VERSION 5.7 ;
  NOWIREEXTENSIONATPIN ON ;
  DIVIDERCHAR "/" ;
  BUSBITCHARS "[]" ;
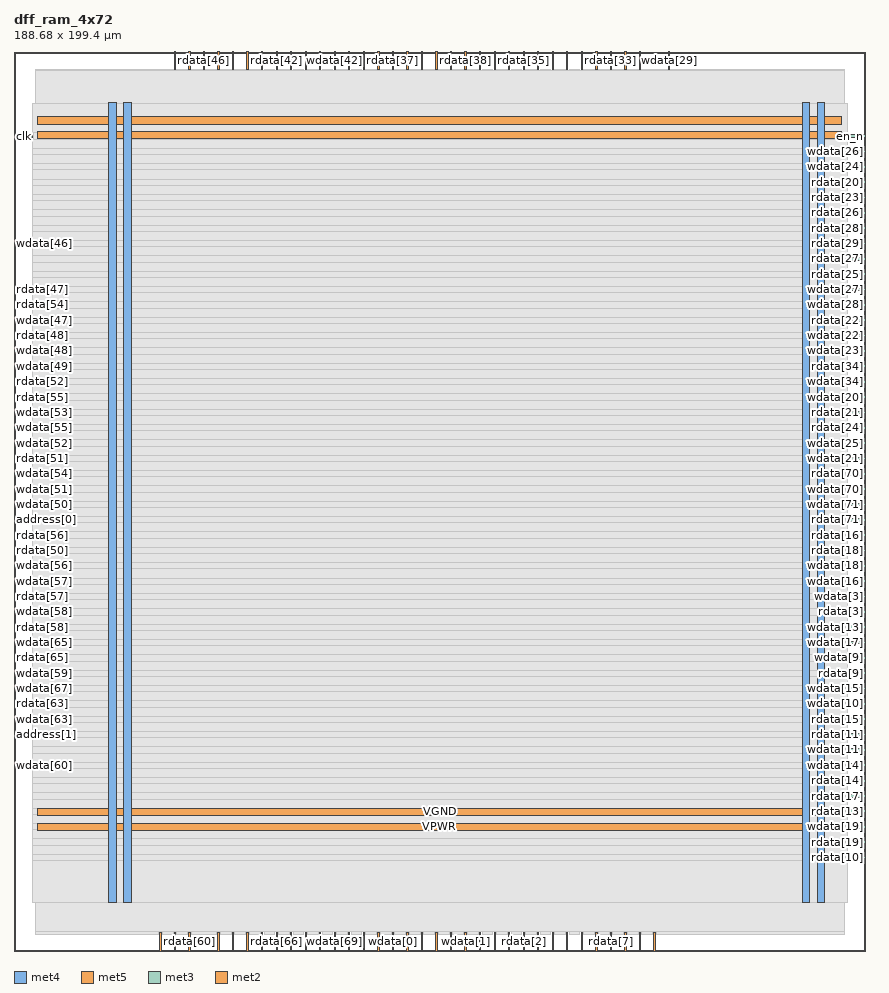
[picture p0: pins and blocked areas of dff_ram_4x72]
MACRO dff_ram_4x72
  CLASS BLOCK ;
  FOREIGN dff_ram_4x72 ;
  ORIGIN 0.000 0.000 ;
  SIZE 188.680 BY 199.400 ;
  PIN VGND
    DIRECTION INOUT ;
    USE GROUND ;
    PORT
      LAYER met4 ;
        RECT 24.340 10.640 25.940 187.920 ;
    END
    PORT
      LAYER met4 ;
        RECT 177.940 10.640 179.540 187.920 ;
    END
    PORT
      LAYER met5 ;
        RECT 5.280 30.030 183.320 31.630 ;
    END
    PORT
      LAYER met5 ;
        RECT 5.280 183.210 183.320 184.810 ;
    END
  END VGND
  PIN VPWR
    DIRECTION INOUT ;
    USE POWER ;
    PORT
      LAYER met4 ;
        RECT 21.040 10.640 22.640 187.920 ;
    END
    PORT
      LAYER met4 ;
        RECT 174.640 10.640 176.240 187.920 ;
    END
    PORT
      LAYER met5 ;
        RECT 5.280 26.730 183.320 28.330 ;
    END
    PORT
      LAYER met5 ;
        RECT 5.280 179.910 183.320 181.510 ;
    END
  END VPWR
  PIN address[0]
    DIRECTION INPUT ;
    USE SIGNAL ;
    ANTENNAGATEAREA 0.213000 ;
    PORT
      LAYER met3 ;
        RECT 0.000 95.240 4.000 95.840 ;
    END
  END address[0]
  PIN address[1]
    DIRECTION INPUT ;
    USE SIGNAL ;
    ANTENNAGATEAREA 0.213000 ;
    PORT
      LAYER met3 ;
        RECT 0.000 47.640 4.000 48.240 ;
    END
  END address[1]
  PIN clk
    DIRECTION INPUT ;
    USE SIGNAL ;
    ANTENNAGATEAREA 0.852000 ;
    PORT
      LAYER met3 ;
        RECT 0.000 180.240 4.000 180.840 ;
    END
  END clk
  PIN en_n
    DIRECTION INPUT ;
    USE SIGNAL ;
    ANTENNAGATEAREA 0.196500 ;
    PORT
      LAYER met3 ;
        RECT 184.680 180.240 188.680 180.840 ;
    END
  END en_n
  PIN rdata[0]
    DIRECTION OUTPUT TRISTATE ;
    USE SIGNAL ;
    ANTENNADIFFAREA 0.795200 ;
    PORT
      LAYER met2 ;
        RECT 116.010 0.000 116.290 4.000 ;
    END
  END rdata[0]
  PIN rdata[10]
    DIRECTION OUTPUT TRISTATE ;
    USE SIGNAL ;
    ANTENNADIFFAREA 0.445500 ;
    PORT
      LAYER met3 ;
        RECT 184.680 20.440 188.680 21.040 ;
    END
  END rdata[10]
  PIN rdata[11]
    DIRECTION OUTPUT TRISTATE ;
    USE SIGNAL ;
    ANTENNADIFFAREA 0.795200 ;
    PORT
      LAYER met3 ;
        RECT 184.680 47.640 188.680 48.240 ;
    END
  END rdata[11]
  PIN rdata[12]
    DIRECTION OUTPUT TRISTATE ;
    USE SIGNAL ;
    ANTENNADIFFAREA 0.795200 ;
    PORT
      LAYER met2 ;
        RECT 141.770 0.000 142.050 4.000 ;
    END
  END rdata[12]
  PIN rdata[13]
    DIRECTION OUTPUT TRISTATE ;
    USE SIGNAL ;
    ANTENNADIFFAREA 0.445500 ;
    PORT
      LAYER met3 ;
        RECT 184.680 30.640 188.680 31.240 ;
    END
  END rdata[13]
  PIN rdata[14]
    DIRECTION OUTPUT TRISTATE ;
    USE SIGNAL ;
    ANTENNADIFFAREA 0.795200 ;
    PORT
      LAYER met3 ;
        RECT 184.680 37.440 188.680 38.040 ;
    END
  END rdata[14]
  PIN rdata[15]
    DIRECTION OUTPUT TRISTATE ;
    USE SIGNAL ;
    ANTENNADIFFAREA 0.445500 ;
    PORT
      LAYER met3 ;
        RECT 184.680 51.040 188.680 51.640 ;
    END
  END rdata[15]
  PIN rdata[16]
    DIRECTION OUTPUT TRISTATE ;
    USE SIGNAL ;
    ANTENNADIFFAREA 0.795200 ;
    PORT
      LAYER met3 ;
        RECT 184.680 91.840 188.680 92.440 ;
    END
  END rdata[16]
  PIN rdata[17]
    DIRECTION OUTPUT TRISTATE ;
    USE SIGNAL ;
    ANTENNADIFFAREA 0.445500 ;
    PORT
      LAYER met3 ;
        RECT 184.680 34.040 188.680 34.640 ;
    END
  END rdata[17]
  PIN rdata[18]
    DIRECTION OUTPUT TRISTATE ;
    USE SIGNAL ;
    ANTENNADIFFAREA 0.445500 ;
    PORT
      LAYER met3 ;
        RECT 184.680 88.440 188.680 89.040 ;
    END
  END rdata[18]
  PIN rdata[19]
    DIRECTION OUTPUT TRISTATE ;
    USE SIGNAL ;
    ANTENNADIFFAREA 0.445500 ;
    PORT
      LAYER met3 ;
        RECT 184.680 23.840 188.680 24.440 ;
    END
  END rdata[19]
  PIN rdata[1]
    DIRECTION OUTPUT TRISTATE ;
    USE SIGNAL ;
    ANTENNADIFFAREA 0.795200 ;
    PORT
      LAYER met2 ;
        RECT 109.570 0.000 109.850 4.000 ;
    END
  END rdata[1]
  PIN rdata[20]
    DIRECTION OUTPUT TRISTATE ;
    USE SIGNAL ;
    ANTENNADIFFAREA 0.795200 ;
    PORT
      LAYER met3 ;
        RECT 184.680 170.040 188.680 170.640 ;
    END
  END rdata[20]
  PIN rdata[21]
    DIRECTION OUTPUT TRISTATE ;
    USE SIGNAL ;
    ANTENNADIFFAREA 0.795200 ;
    PORT
      LAYER met3 ;
        RECT 184.680 119.040 188.680 119.640 ;
    END
  END rdata[21]
  PIN rdata[22]
    DIRECTION OUTPUT TRISTATE ;
    USE SIGNAL ;
    ANTENNADIFFAREA 0.445500 ;
    PORT
      LAYER met3 ;
        RECT 184.680 139.440 188.680 140.040 ;
    END
  END rdata[22]
  PIN rdata[23]
    DIRECTION OUTPUT TRISTATE ;
    USE SIGNAL ;
    ANTENNADIFFAREA 0.445500 ;
    PORT
      LAYER met3 ;
        RECT 184.680 166.640 188.680 167.240 ;
    END
  END rdata[23]
  PIN rdata[24]
    DIRECTION OUTPUT TRISTATE ;
    USE SIGNAL ;
    ANTENNADIFFAREA 0.445500 ;
    PORT
      LAYER met3 ;
        RECT 184.680 115.640 188.680 116.240 ;
    END
  END rdata[24]
  PIN rdata[25]
    DIRECTION OUTPUT TRISTATE ;
    USE SIGNAL ;
    ANTENNADIFFAREA 0.795200 ;
    PORT
      LAYER met3 ;
        RECT 184.680 149.640 188.680 150.240 ;
    END
  END rdata[25]
  PIN rdata[26]
    DIRECTION OUTPUT TRISTATE ;
    USE SIGNAL ;
    ANTENNADIFFAREA 0.445500 ;
    PORT
      LAYER met3 ;
        RECT 184.680 163.240 188.680 163.840 ;
    END
  END rdata[26]
  PIN rdata[27]
    DIRECTION OUTPUT TRISTATE ;
    USE SIGNAL ;
    ANTENNADIFFAREA 0.795200 ;
    PORT
      LAYER met3 ;
        RECT 184.680 153.040 188.680 153.640 ;
    END
  END rdata[27]
  PIN rdata[28]
    DIRECTION OUTPUT TRISTATE ;
    USE SIGNAL ;
    ANTENNADIFFAREA 0.795200 ;
    PORT
      LAYER met3 ;
        RECT 184.680 159.840 188.680 160.440 ;
    END
  END rdata[28]
  PIN rdata[29]
    DIRECTION OUTPUT TRISTATE ;
    USE SIGNAL ;
    ANTENNADIFFAREA 0.795200 ;
    PORT
      LAYER met3 ;
        RECT 184.680 156.440 188.680 157.040 ;
    END
  END rdata[29]
  PIN rdata[2]
    DIRECTION OUTPUT TRISTATE ;
    USE SIGNAL ;
    ANTENNADIFFAREA 0.795200 ;
    PORT
      LAYER met2 ;
        RECT 112.790 0.000 113.070 4.000 ;
    END
  END rdata[2]
  PIN rdata[30]
    DIRECTION OUTPUT TRISTATE ;
    USE SIGNAL ;
    ANTENNADIFFAREA 0.795200 ;
    PORT
      LAYER met2 ;
        RECT 138.550 195.400 138.830 199.400 ;
    END
  END rdata[30]
  PIN rdata[31]
    DIRECTION OUTPUT TRISTATE ;
    USE SIGNAL ;
    ANTENNADIFFAREA 0.795200 ;
    PORT
      LAYER met2 ;
        RECT 135.330 195.400 135.610 199.400 ;
    END
  END rdata[31]
  PIN rdata[32]
    DIRECTION OUTPUT TRISTATE ;
    USE SIGNAL ;
    ANTENNADIFFAREA 0.795200 ;
    PORT
      LAYER met2 ;
        RECT 128.890 195.400 129.170 199.400 ;
    END
  END rdata[32]
  PIN rdata[33]
    DIRECTION OUTPUT TRISTATE ;
    USE SIGNAL ;
    ANTENNADIFFAREA 0.795200 ;
    PORT
      LAYER met2 ;
        RECT 132.110 195.400 132.390 199.400 ;
    END
  END rdata[33]
  PIN rdata[34]
    DIRECTION OUTPUT TRISTATE ;
    USE SIGNAL ;
    ANTENNADIFFAREA 0.795200 ;
    PORT
      LAYER met3 ;
        RECT 184.680 129.240 188.680 129.840 ;
    END
  END rdata[34]
  PIN rdata[35]
    DIRECTION OUTPUT TRISTATE ;
    USE SIGNAL ;
    ANTENNADIFFAREA 0.795200 ;
    PORT
      LAYER met2 ;
        RECT 112.790 195.400 113.070 199.400 ;
    END
  END rdata[35]
  PIN rdata[36]
    DIRECTION OUTPUT TRISTATE ;
    USE SIGNAL ;
    ANTENNADIFFAREA 0.795200 ;
    PORT
      LAYER met2 ;
        RECT 106.350 195.400 106.630 199.400 ;
    END
  END rdata[36]
  PIN rdata[37]
    DIRECTION OUTPUT TRISTATE ;
    USE SIGNAL ;
    ANTENNADIFFAREA 0.795200 ;
    PORT
      LAYER met2 ;
        RECT 83.810 195.400 84.090 199.400 ;
    END
  END rdata[37]
  PIN rdata[38]
    DIRECTION OUTPUT TRISTATE ;
    USE SIGNAL ;
    ANTENNADIFFAREA 0.795200 ;
    PORT
      LAYER met2 ;
        RECT 99.910 195.400 100.190 199.400 ;
    END
  END rdata[38]
  PIN rdata[39]
    DIRECTION OUTPUT TRISTATE ;
    USE SIGNAL ;
    ANTENNADIFFAREA 0.795200 ;
    PORT
      LAYER met2 ;
        RECT 103.130 195.400 103.410 199.400 ;
    END
  END rdata[39]
  PIN rdata[3]
    DIRECTION OUTPUT TRISTATE ;
    USE SIGNAL ;
    ANTENNADIFFAREA 0.445500 ;
    PORT
      LAYER met3 ;
        RECT 184.680 74.840 188.680 75.440 ;
    END
  END rdata[3]
  PIN rdata[40]
    DIRECTION OUTPUT TRISTATE ;
    USE SIGNAL ;
    ANTENNADIFFAREA 0.795200 ;
    PORT
      LAYER met2 ;
        RECT 45.170 195.400 45.450 199.400 ;
    END
  END rdata[40]
  PIN rdata[41]
    DIRECTION OUTPUT TRISTATE ;
    USE SIGNAL ;
    ANTENNADIFFAREA 0.795200 ;
    PORT
      LAYER met2 ;
        RECT 77.370 195.400 77.650 199.400 ;
    END
  END rdata[41]
  PIN rdata[42]
    DIRECTION OUTPUT TRISTATE ;
    USE SIGNAL ;
    ANTENNADIFFAREA 0.795200 ;
    PORT
      LAYER met2 ;
        RECT 58.050 195.400 58.330 199.400 ;
    END
  END rdata[42]
  PIN rdata[43]
    DIRECTION OUTPUT TRISTATE ;
    USE SIGNAL ;
    ANTENNADIFFAREA 0.795200 ;
    PORT
      LAYER met2 ;
        RECT 54.830 195.400 55.110 199.400 ;
    END
  END rdata[43]
  PIN rdata[44]
    DIRECTION OUTPUT TRISTATE ;
    USE SIGNAL ;
    ANTENNADIFFAREA 0.795200 ;
    PORT
      LAYER met2 ;
        RECT 38.730 195.400 39.010 199.400 ;
    END
  END rdata[44]
  PIN rdata[45]
    DIRECTION OUTPUT TRISTATE ;
    USE SIGNAL ;
    ANTENNADIFFAREA 0.795200 ;
    PORT
      LAYER met2 ;
        RECT 61.270 195.400 61.550 199.400 ;
    END
  END rdata[45]
  PIN rdata[46]
    DIRECTION OUTPUT TRISTATE ;
    USE SIGNAL ;
    ANTENNADIFFAREA 0.795200 ;
    PORT
      LAYER met2 ;
        RECT 41.950 195.400 42.230 199.400 ;
    END
  END rdata[46]
  PIN rdata[47]
    DIRECTION OUTPUT TRISTATE ;
    USE SIGNAL ;
    ANTENNADIFFAREA 0.795200 ;
    PORT
      LAYER met3 ;
        RECT 0.000 146.240 4.000 146.840 ;
    END
  END rdata[47]
  PIN rdata[48]
    DIRECTION OUTPUT TRISTATE ;
    USE SIGNAL ;
    ANTENNADIFFAREA 0.795200 ;
    PORT
      LAYER met3 ;
        RECT 0.000 136.040 4.000 136.640 ;
    END
  END rdata[48]
  PIN rdata[49]
    DIRECTION OUTPUT TRISTATE ;
    USE SIGNAL ;
    ANTENNADIFFAREA 0.795200 ;
    PORT
      LAYER met2 ;
        RECT 64.490 195.400 64.770 199.400 ;
    END
  END rdata[49]
  PIN rdata[4]
    DIRECTION OUTPUT TRISTATE ;
    USE SIGNAL ;
    ANTENNADIFFAREA 0.795200 ;
    PORT
      LAYER met2 ;
        RECT 106.350 0.000 106.630 4.000 ;
    END
  END rdata[4]
  PIN rdata[50]
    DIRECTION OUTPUT TRISTATE ;
    USE SIGNAL ;
    ANTENNADIFFAREA 0.795200 ;
    PORT
      LAYER met3 ;
        RECT 0.000 88.440 4.000 89.040 ;
    END
  END rdata[50]
  PIN rdata[51]
    DIRECTION OUTPUT TRISTATE ;
    USE SIGNAL ;
    ANTENNADIFFAREA 0.795200 ;
    PORT
      LAYER met3 ;
        RECT 0.000 108.840 4.000 109.440 ;
    END
  END rdata[51]
  PIN rdata[52]
    DIRECTION OUTPUT TRISTATE ;
    USE SIGNAL ;
    ANTENNADIFFAREA 0.795200 ;
    PORT
      LAYER met3 ;
        RECT 0.000 125.840 4.000 126.440 ;
    END
  END rdata[52]
  PIN rdata[53]
    DIRECTION OUTPUT TRISTATE ;
    USE SIGNAL ;
    ANTENNADIFFAREA 0.795200 ;
    PORT
      LAYER met2 ;
        RECT 80.590 195.400 80.870 199.400 ;
    END
  END rdata[53]
  PIN rdata[54]
    DIRECTION OUTPUT TRISTATE ;
    USE SIGNAL ;
    ANTENNADIFFAREA 0.795200 ;
    PORT
      LAYER met3 ;
        RECT 0.000 142.840 4.000 143.440 ;
    END
  END rdata[54]
  PIN rdata[55]
    DIRECTION OUTPUT TRISTATE ;
    USE SIGNAL ;
    ANTENNADIFFAREA 0.795200 ;
    PORT
      LAYER met3 ;
        RECT 0.000 122.440 4.000 123.040 ;
    END
  END rdata[55]
  PIN rdata[56]
    DIRECTION OUTPUT TRISTATE ;
    USE SIGNAL ;
    ANTENNADIFFAREA 0.795200 ;
    PORT
      LAYER met3 ;
        RECT 0.000 91.840 4.000 92.440 ;
    END
  END rdata[56]
  PIN rdata[57]
    DIRECTION OUTPUT TRISTATE ;
    USE SIGNAL ;
    ANTENNADIFFAREA 0.795200 ;
    PORT
      LAYER met3 ;
        RECT 0.000 78.240 4.000 78.840 ;
    END
  END rdata[57]
  PIN rdata[58]
    DIRECTION OUTPUT TRISTATE ;
    USE SIGNAL ;
    ANTENNADIFFAREA 0.795200 ;
    PORT
      LAYER met3 ;
        RECT 0.000 71.440 4.000 72.040 ;
    END
  END rdata[58]
  PIN rdata[59]
    DIRECTION OUTPUT TRISTATE ;
    USE SIGNAL ;
    ANTENNADIFFAREA 0.795200 ;
    PORT
      LAYER met2 ;
        RECT 80.590 0.000 80.870 4.000 ;
    END
  END rdata[59]
  PIN rdata[5]
    DIRECTION OUTPUT TRISTATE ;
    USE SIGNAL ;
    ANTENNADIFFAREA 0.795200 ;
    PORT
      LAYER met2 ;
        RECT 103.130 0.000 103.410 4.000 ;
    END
  END rdata[5]
  PIN rdata[60]
    DIRECTION OUTPUT TRISTATE ;
    USE SIGNAL ;
    ANTENNADIFFAREA 0.795200 ;
    PORT
      LAYER met2 ;
        RECT 38.730 0.000 39.010 4.000 ;
    END
  END rdata[60]
  PIN rdata[61]
    DIRECTION OUTPUT TRISTATE ;
    USE SIGNAL ;
    ANTENNADIFFAREA 0.795200 ;
    PORT
      LAYER met2 ;
        RECT 45.170 0.000 45.450 4.000 ;
    END
  END rdata[61]
  PIN rdata[62]
    DIRECTION OUTPUT TRISTATE ;
    USE SIGNAL ;
    ANTENNADIFFAREA 0.795200 ;
    PORT
      LAYER met2 ;
        RECT 77.370 0.000 77.650 4.000 ;
    END
  END rdata[62]
  PIN rdata[63]
    DIRECTION OUTPUT TRISTATE ;
    USE SIGNAL ;
    ANTENNADIFFAREA 0.795200 ;
    PORT
      LAYER met3 ;
        RECT 0.000 54.440 4.000 55.040 ;
    END
  END rdata[63]
  PIN rdata[64]
    DIRECTION OUTPUT TRISTATE ;
    USE SIGNAL ;
    ANTENNADIFFAREA 0.795200 ;
    PORT
      LAYER met2 ;
        RECT 35.510 0.000 35.790 4.000 ;
    END
  END rdata[64]
  PIN rdata[65]
    DIRECTION OUTPUT TRISTATE ;
    USE SIGNAL ;
    ANTENNADIFFAREA 0.795200 ;
    PORT
      LAYER met3 ;
        RECT 0.000 64.640 4.000 65.240 ;
    END
  END rdata[65]
  PIN rdata[66]
    DIRECTION OUTPUT TRISTATE ;
    USE SIGNAL ;
    ANTENNADIFFAREA 0.795200 ;
    PORT
      LAYER met2 ;
        RECT 58.050 0.000 58.330 4.000 ;
    END
  END rdata[66]
  PIN rdata[67]
    DIRECTION OUTPUT TRISTATE ;
    USE SIGNAL ;
    ANTENNADIFFAREA 0.795200 ;
    PORT
      LAYER met2 ;
        RECT 48.390 0.000 48.670 4.000 ;
    END
  END rdata[67]
  PIN rdata[68]
    DIRECTION OUTPUT TRISTATE ;
    USE SIGNAL ;
    ANTENNADIFFAREA 0.795200 ;
    PORT
      LAYER met2 ;
        RECT 61.270 0.000 61.550 4.000 ;
    END
  END rdata[68]
  PIN rdata[69]
    DIRECTION OUTPUT TRISTATE ;
    USE SIGNAL ;
    ANTENNADIFFAREA 0.795200 ;
    PORT
      LAYER met2 ;
        RECT 64.490 0.000 64.770 4.000 ;
    END
  END rdata[69]
  PIN rdata[6]
    DIRECTION OUTPUT TRISTATE ;
    USE SIGNAL ;
    ANTENNADIFFAREA 0.795200 ;
    PORT
      LAYER met2 ;
        RECT 135.330 0.000 135.610 4.000 ;
    END
  END rdata[6]
  PIN rdata[70]
    DIRECTION OUTPUT TRISTATE ;
    USE SIGNAL ;
    ANTENNADIFFAREA 0.795200 ;
    PORT
      LAYER met3 ;
        RECT 184.680 105.440 188.680 106.040 ;
    END
  END rdata[70]
  PIN rdata[71]
    DIRECTION OUTPUT TRISTATE ;
    USE SIGNAL ;
    ANTENNADIFFAREA 0.795200 ;
    PORT
      LAYER met3 ;
        RECT 184.680 95.240 188.680 95.840 ;
    END
  END rdata[71]
  PIN rdata[7]
    DIRECTION OUTPUT TRISTATE ;
    USE SIGNAL ;
    ANTENNADIFFAREA 0.795200 ;
    PORT
      LAYER met2 ;
        RECT 132.110 0.000 132.390 4.000 ;
    END
  END rdata[7]
  PIN rdata[8]
    DIRECTION OUTPUT TRISTATE ;
    USE SIGNAL ;
    ANTENNADIFFAREA 0.795200 ;
    PORT
      LAYER met2 ;
        RECT 128.890 0.000 129.170 4.000 ;
    END
  END rdata[8]
  PIN rdata[9]
    DIRECTION OUTPUT TRISTATE ;
    USE SIGNAL ;
    ANTENNADIFFAREA 0.795200 ;
    PORT
      LAYER met3 ;
        RECT 184.680 61.240 188.680 61.840 ;
    END
  END rdata[9]
  PIN wdata[0]
    DIRECTION INPUT ;
    USE SIGNAL ;
    ANTENNAGATEAREA 0.196500 ;
    PORT
      LAYER met2 ;
        RECT 83.810 0.000 84.090 4.000 ;
    END
  END wdata[0]
  PIN wdata[10]
    DIRECTION INPUT ;
    USE SIGNAL ;
    ANTENNAGATEAREA 0.196500 ;
    PORT
      LAYER met3 ;
        RECT 184.680 54.440 188.680 55.040 ;
    END
  END wdata[10]
  PIN wdata[11]
    DIRECTION INPUT ;
    USE SIGNAL ;
    ANTENNAGATEAREA 0.196500 ;
    PORT
      LAYER met3 ;
        RECT 184.680 44.240 188.680 44.840 ;
    END
  END wdata[11]
  PIN wdata[12]
    DIRECTION INPUT ;
    USE SIGNAL ;
    ANTENNAGATEAREA 0.196500 ;
    PORT
      LAYER met2 ;
        RECT 138.550 0.000 138.830 4.000 ;
    END
  END wdata[12]
  PIN wdata[13]
    DIRECTION INPUT ;
    USE SIGNAL ;
    ANTENNAGATEAREA 0.196500 ;
    PORT
      LAYER met3 ;
        RECT 184.680 71.440 188.680 72.040 ;
    END
  END wdata[13]
  PIN wdata[14]
    DIRECTION INPUT ;
    USE SIGNAL ;
    ANTENNAGATEAREA 0.196500 ;
    PORT
      LAYER met3 ;
        RECT 184.680 40.840 188.680 41.440 ;
    END
  END wdata[14]
  PIN wdata[15]
    DIRECTION INPUT ;
    USE SIGNAL ;
    ANTENNAGATEAREA 0.196500 ;
    PORT
      LAYER met3 ;
        RECT 184.680 57.840 188.680 58.440 ;
    END
  END wdata[15]
  PIN wdata[16]
    DIRECTION INPUT ;
    USE SIGNAL ;
    ANTENNAGATEAREA 0.196500 ;
    PORT
      LAYER met3 ;
        RECT 184.680 81.640 188.680 82.240 ;
    END
  END wdata[16]
  PIN wdata[17]
    DIRECTION INPUT ;
    USE SIGNAL ;
    ANTENNAGATEAREA 0.196500 ;
    PORT
      LAYER met3 ;
        RECT 184.680 68.040 188.680 68.640 ;
    END
  END wdata[17]
  PIN wdata[18]
    DIRECTION INPUT ;
    USE SIGNAL ;
    ANTENNAGATEAREA 0.196500 ;
    PORT
      LAYER met3 ;
        RECT 184.680 85.040 188.680 85.640 ;
    END
  END wdata[18]
  PIN wdata[19]
    DIRECTION INPUT ;
    USE SIGNAL ;
    ANTENNAGATEAREA 0.196500 ;
    PORT
      LAYER met3 ;
        RECT 184.680 27.240 188.680 27.840 ;
    END
  END wdata[19]
  PIN wdata[1]
    DIRECTION INPUT ;
    USE SIGNAL ;
    ANTENNAGATEAREA 0.196500 ;
    PORT
      LAYER met2 ;
        RECT 99.910 0.000 100.190 4.000 ;
    END
  END wdata[1]
  PIN wdata[20]
    DIRECTION INPUT ;
    USE SIGNAL ;
    ANTENNAGATEAREA 0.196500 ;
    PORT
      LAYER met3 ;
        RECT 184.680 122.440 188.680 123.040 ;
    END
  END wdata[20]
  PIN wdata[21]
    DIRECTION INPUT ;
    USE SIGNAL ;
    ANTENNAGATEAREA 0.196500 ;
    PORT
      LAYER met3 ;
        RECT 184.680 108.840 188.680 109.440 ;
    END
  END wdata[21]
  PIN wdata[22]
    DIRECTION INPUT ;
    USE SIGNAL ;
    ANTENNAGATEAREA 0.196500 ;
    PORT
      LAYER met3 ;
        RECT 184.680 136.040 188.680 136.640 ;
    END
  END wdata[22]
  PIN wdata[23]
    DIRECTION INPUT ;
    USE SIGNAL ;
    ANTENNAGATEAREA 0.196500 ;
    PORT
      LAYER met3 ;
        RECT 184.680 132.640 188.680 133.240 ;
    END
  END wdata[23]
  PIN wdata[24]
    DIRECTION INPUT ;
    USE SIGNAL ;
    ANTENNAGATEAREA 0.196500 ;
    PORT
      LAYER met3 ;
        RECT 184.680 173.440 188.680 174.040 ;
    END
  END wdata[24]
  PIN wdata[25]
    DIRECTION INPUT ;
    USE SIGNAL ;
    ANTENNAGATEAREA 0.196500 ;
    PORT
      LAYER met3 ;
        RECT 184.680 112.240 188.680 112.840 ;
    END
  END wdata[25]
  PIN wdata[26]
    DIRECTION INPUT ;
    USE SIGNAL ;
    ANTENNAGATEAREA 0.196500 ;
    PORT
      LAYER met3 ;
        RECT 184.680 176.840 188.680 177.440 ;
    END
  END wdata[26]
  PIN wdata[27]
    DIRECTION INPUT ;
    USE SIGNAL ;
    ANTENNAGATEAREA 0.196500 ;
    PORT
      LAYER met3 ;
        RECT 184.680 146.240 188.680 146.840 ;
    END
  END wdata[27]
  PIN wdata[28]
    DIRECTION INPUT ;
    USE SIGNAL ;
    ANTENNAGATEAREA 0.196500 ;
    PORT
      LAYER met3 ;
        RECT 184.680 142.840 188.680 143.440 ;
    END
  END wdata[28]
  PIN wdata[29]
    DIRECTION INPUT ;
    USE SIGNAL ;
    ANTENNAGATEAREA 0.196500 ;
    PORT
      LAYER met2 ;
        RECT 144.990 195.400 145.270 199.400 ;
    END
  END wdata[29]
  PIN wdata[2]
    DIRECTION INPUT ;
    USE SIGNAL ;
    ANTENNAGATEAREA 0.196500 ;
    PORT
      LAYER met2 ;
        RECT 96.690 0.000 96.970 4.000 ;
    END
  END wdata[2]
  PIN wdata[30]
    DIRECTION INPUT ;
    USE SIGNAL ;
    ANTENNAGATEAREA 0.196500 ;
    PORT
      LAYER met2 ;
        RECT 119.230 195.400 119.510 199.400 ;
    END
  END wdata[30]
  PIN wdata[31]
    DIRECTION INPUT ;
    USE SIGNAL ;
    ANTENNAGATEAREA 0.196500 ;
    PORT
      LAYER met2 ;
        RECT 125.670 195.400 125.950 199.400 ;
    END
  END wdata[31]
  PIN wdata[32]
    DIRECTION INPUT ;
    USE SIGNAL ;
    ANTENNAGATEAREA 0.196500 ;
    PORT
      LAYER met2 ;
        RECT 116.010 195.400 116.290 199.400 ;
    END
  END wdata[32]
  PIN wdata[33]
    DIRECTION INPUT ;
    USE SIGNAL ;
    ANTENNAGATEAREA 0.196500 ;
    PORT
      LAYER met2 ;
        RECT 122.450 195.400 122.730 199.400 ;
    END
  END wdata[33]
  PIN wdata[34]
    DIRECTION INPUT ;
    USE SIGNAL ;
    ANTENNAGATEAREA 0.196500 ;
    PORT
      LAYER met3 ;
        RECT 184.680 125.840 188.680 126.440 ;
    END
  END wdata[34]
  PIN wdata[35]
    DIRECTION INPUT ;
    USE SIGNAL ;
    ANTENNAGATEAREA 0.196500 ;
    PORT
      LAYER met2 ;
        RECT 109.570 195.400 109.850 199.400 ;
    END
  END wdata[35]
  PIN wdata[36]
    DIRECTION INPUT ;
    USE SIGNAL ;
    ANTENNAGATEAREA 0.196500 ;
    PORT
      LAYER met2 ;
        RECT 96.690 195.400 96.970 199.400 ;
    END
  END wdata[36]
  PIN wdata[37]
    DIRECTION INPUT ;
    USE SIGNAL ;
    ANTENNAGATEAREA 0.196500 ;
    PORT
      LAYER met2 ;
        RECT 90.250 195.400 90.530 199.400 ;
    END
  END wdata[37]
  PIN wdata[38]
    DIRECTION INPUT ;
    USE SIGNAL ;
    ANTENNAGATEAREA 0.196500 ;
    PORT
      LAYER met2 ;
        RECT 93.470 195.400 93.750 199.400 ;
    END
  END wdata[38]
  PIN wdata[39]
    DIRECTION INPUT ;
    USE SIGNAL ;
    ANTENNAGATEAREA 0.196500 ;
    PORT
      LAYER met2 ;
        RECT 87.030 195.400 87.310 199.400 ;
    END
  END wdata[39]
  PIN wdata[3]
    DIRECTION INPUT ;
    USE SIGNAL ;
    ANTENNAGATEAREA 0.196500 ;
    PORT
      LAYER met3 ;
        RECT 184.680 78.240 188.680 78.840 ;
    END
  END wdata[3]
  PIN wdata[40]
    DIRECTION INPUT ;
    USE SIGNAL ;
    ANTENNAGATEAREA 0.196500 ;
    PORT
      LAYER met2 ;
        RECT 48.390 195.400 48.670 199.400 ;
    END
  END wdata[40]
  PIN wdata[41]
    DIRECTION INPUT ;
    USE SIGNAL ;
    ANTENNAGATEAREA 0.196500 ;
    PORT
      LAYER met2 ;
        RECT 74.150 195.400 74.430 199.400 ;
    END
  END wdata[41]
  PIN wdata[42]
    DIRECTION INPUT ;
    USE SIGNAL ;
    ANTENNAGATEAREA 0.196500 ;
    PORT
      LAYER met2 ;
        RECT 70.930 195.400 71.210 199.400 ;
    END
  END wdata[42]
  PIN wdata[43]
    DIRECTION INPUT ;
    USE SIGNAL ;
    ANTENNAGATEAREA 0.196500 ;
    PORT
      LAYER met2 ;
        RECT 51.610 195.400 51.890 199.400 ;
    END
  END wdata[43]
  PIN wdata[44]
    DIRECTION INPUT ;
    USE SIGNAL ;
    ANTENNAGATEAREA 0.196500 ;
    PORT
      LAYER met2 ;
        RECT 35.510 195.400 35.790 199.400 ;
    END
  END wdata[44]
  PIN wdata[45]
    DIRECTION INPUT ;
    USE SIGNAL ;
    ANTENNAGATEAREA 0.196500 ;
    PORT
      LAYER met2 ;
        RECT 67.710 195.400 67.990 199.400 ;
    END
  END wdata[45]
  PIN wdata[46]
    DIRECTION INPUT ;
    USE SIGNAL ;
    ANTENNAGATEAREA 0.196500 ;
    PORT
      LAYER met3 ;
        RECT 0.000 156.440 4.000 157.040 ;
    END
  END wdata[46]
  PIN wdata[47]
    DIRECTION INPUT ;
    USE SIGNAL ;
    ANTENNAGATEAREA 0.196500 ;
    PORT
      LAYER met3 ;
        RECT 0.000 139.440 4.000 140.040 ;
    END
  END wdata[47]
  PIN wdata[48]
    DIRECTION INPUT ;
    USE SIGNAL ;
    ANTENNAGATEAREA 0.196500 ;
    PORT
      LAYER met3 ;
        RECT 0.000 132.640 4.000 133.240 ;
    END
  END wdata[48]
  PIN wdata[49]
    DIRECTION INPUT ;
    USE SIGNAL ;
    ANTENNAGATEAREA 0.196500 ;
    PORT
      LAYER met3 ;
        RECT 0.000 129.240 4.000 129.840 ;
    END
  END wdata[49]
  PIN wdata[4]
    DIRECTION INPUT ;
    USE SIGNAL ;
    ANTENNAGATEAREA 0.196500 ;
    PORT
      LAYER met2 ;
        RECT 87.030 0.000 87.310 4.000 ;
    END
  END wdata[4]
  PIN wdata[50]
    DIRECTION INPUT ;
    USE SIGNAL ;
    ANTENNAGATEAREA 0.196500 ;
    PORT
      LAYER met3 ;
        RECT 0.000 98.640 4.000 99.240 ;
    END
  END wdata[50]
  PIN wdata[51]
    DIRECTION INPUT ;
    USE SIGNAL ;
    ANTENNAGATEAREA 0.196500 ;
    PORT
      LAYER met3 ;
        RECT 0.000 102.040 4.000 102.640 ;
    END
  END wdata[51]
  PIN wdata[52]
    DIRECTION INPUT ;
    USE SIGNAL ;
    ANTENNAGATEAREA 0.196500 ;
    PORT
      LAYER met3 ;
        RECT 0.000 112.240 4.000 112.840 ;
    END
  END wdata[52]
  PIN wdata[53]
    DIRECTION INPUT ;
    USE SIGNAL ;
    ANTENNAGATEAREA 0.196500 ;
    PORT
      LAYER met3 ;
        RECT 0.000 119.040 4.000 119.640 ;
    END
  END wdata[53]
  PIN wdata[54]
    DIRECTION INPUT ;
    USE SIGNAL ;
    ANTENNAGATEAREA 0.196500 ;
    PORT
      LAYER met3 ;
        RECT 0.000 105.440 4.000 106.040 ;
    END
  END wdata[54]
  PIN wdata[55]
    DIRECTION INPUT ;
    USE SIGNAL ;
    ANTENNAGATEAREA 0.196500 ;
    PORT
      LAYER met3 ;
        RECT 0.000 115.640 4.000 116.240 ;
    END
  END wdata[55]
  PIN wdata[56]
    DIRECTION INPUT ;
    USE SIGNAL ;
    ANTENNAGATEAREA 0.196500 ;
    PORT
      LAYER met3 ;
        RECT 0.000 85.040 4.000 85.640 ;
    END
  END wdata[56]
  PIN wdata[57]
    DIRECTION INPUT ;
    USE SIGNAL ;
    ANTENNAGATEAREA 0.196500 ;
    PORT
      LAYER met3 ;
        RECT 0.000 81.640 4.000 82.240 ;
    END
  END wdata[57]
  PIN wdata[58]
    DIRECTION INPUT ;
    USE SIGNAL ;
    ANTENNAGATEAREA 0.196500 ;
    PORT
      LAYER met3 ;
        RECT 0.000 74.840 4.000 75.440 ;
    END
  END wdata[58]
  PIN wdata[59]
    DIRECTION INPUT ;
    USE SIGNAL ;
    ANTENNAGATEAREA 0.196500 ;
    PORT
      LAYER met3 ;
        RECT 0.000 61.240 4.000 61.840 ;
    END
  END wdata[59]
  PIN wdata[5]
    DIRECTION INPUT ;
    USE SIGNAL ;
    ANTENNAGATEAREA 0.196500 ;
    PORT
      LAYER met2 ;
        RECT 93.470 0.000 93.750 4.000 ;
    END
  END wdata[5]
  PIN wdata[60]
    DIRECTION INPUT ;
    USE SIGNAL ;
    ANTENNAGATEAREA 0.196500 ;
    PORT
      LAYER met3 ;
        RECT 0.000 40.840 4.000 41.440 ;
    END
  END wdata[60]
  PIN wdata[61]
    DIRECTION INPUT ;
    USE SIGNAL ;
    ANTENNAGATEAREA 0.196500 ;
    PORT
      LAYER met2 ;
        RECT 54.830 0.000 55.110 4.000 ;
    END
  END wdata[61]
  PIN wdata[62]
    DIRECTION INPUT ;
    USE SIGNAL ;
    ANTENNAGATEAREA 0.196500 ;
    PORT
      LAYER met2 ;
        RECT 67.710 0.000 67.990 4.000 ;
    END
  END wdata[62]
  PIN wdata[63]
    DIRECTION INPUT ;
    USE SIGNAL ;
    ANTENNAGATEAREA 0.196500 ;
    PORT
      LAYER met3 ;
        RECT 0.000 51.040 4.000 51.640 ;
    END
  END wdata[63]
  PIN wdata[64]
    DIRECTION INPUT ;
    USE SIGNAL ;
    ANTENNAGATEAREA 0.196500 ;
    PORT
      LAYER met2 ;
        RECT 32.290 0.000 32.570 4.000 ;
    END
  END wdata[64]
  PIN wdata[65]
    DIRECTION INPUT ;
    USE SIGNAL ;
    ANTENNAGATEAREA 0.196500 ;
    PORT
      LAYER met3 ;
        RECT 0.000 68.040 4.000 68.640 ;
    END
  END wdata[65]
  PIN wdata[66]
    DIRECTION INPUT ;
    USE SIGNAL ;
    ANTENNAGATEAREA 0.196500 ;
    PORT
      LAYER met2 ;
        RECT 51.610 0.000 51.890 4.000 ;
    END
  END wdata[66]
  PIN wdata[67]
    DIRECTION INPUT ;
    USE SIGNAL ;
    ANTENNAGATEAREA 0.196500 ;
    PORT
      LAYER met3 ;
        RECT 0.000 57.840 4.000 58.440 ;
    END
  END wdata[67]
  PIN wdata[68]
    DIRECTION INPUT ;
    USE SIGNAL ;
    ANTENNAGATEAREA 0.196500 ;
    PORT
      LAYER met2 ;
        RECT 74.150 0.000 74.430 4.000 ;
    END
  END wdata[68]
  PIN wdata[69]
    DIRECTION INPUT ;
    USE SIGNAL ;
    ANTENNAGATEAREA 0.196500 ;
    PORT
      LAYER met2 ;
        RECT 70.930 0.000 71.210 4.000 ;
    END
  END wdata[69]
  PIN wdata[6]
    DIRECTION INPUT ;
    USE SIGNAL ;
    ANTENNAGATEAREA 0.196500 ;
    PORT
      LAYER met2 ;
        RECT 125.670 0.000 125.950 4.000 ;
    END
  END wdata[6]
  PIN wdata[70]
    DIRECTION INPUT ;
    USE SIGNAL ;
    ANTENNAGATEAREA 0.196500 ;
    PORT
      LAYER met3 ;
        RECT 184.680 102.040 188.680 102.640 ;
    END
  END wdata[70]
  PIN wdata[71]
    DIRECTION INPUT ;
    USE SIGNAL ;
    ANTENNAGATEAREA 0.196500 ;
    PORT
      LAYER met3 ;
        RECT 184.680 98.640 188.680 99.240 ;
    END
  END wdata[71]
  PIN wdata[7]
    DIRECTION INPUT ;
    USE SIGNAL ;
    ANTENNAGATEAREA 0.196500 ;
    PORT
      LAYER met2 ;
        RECT 122.450 0.000 122.730 4.000 ;
    END
  END wdata[7]
  PIN wdata[8]
    DIRECTION INPUT ;
    USE SIGNAL ;
    ANTENNAGATEAREA 0.196500 ;
    PORT
      LAYER met2 ;
        RECT 119.230 0.000 119.510 4.000 ;
    END
  END wdata[8]
  PIN wdata[9]
    DIRECTION INPUT ;
    USE SIGNAL ;
    ANTENNAGATEAREA 0.196500 ;
    PORT
      LAYER met3 ;
        RECT 184.680 64.640 188.680 65.240 ;
    END
  END wdata[9]
  PIN wr
    DIRECTION INPUT ;
    USE SIGNAL ;
    ANTENNAGATEAREA 0.196500 ;
    PORT
      LAYER met2 ;
        RECT 90.250 0.000 90.530 4.000 ;
    END
  END wr
  OBS
      LAYER li1 ;
        RECT 5.520 10.795 183.080 187.765 ;
      LAYER met1 ;
        RECT 4.670 10.640 183.930 187.920 ;
      LAYER met2 ;
        RECT 4.690 195.120 35.230 195.400 ;
        RECT 36.070 195.120 38.450 195.400 ;
        RECT 39.290 195.120 41.670 195.400 ;
        RECT 42.510 195.120 44.890 195.400 ;
        RECT 45.730 195.120 48.110 195.400 ;
        RECT 48.950 195.120 51.330 195.400 ;
        RECT 52.170 195.120 54.550 195.400 ;
        RECT 55.390 195.120 57.770 195.400 ;
        RECT 58.610 195.120 60.990 195.400 ;
        RECT 61.830 195.120 64.210 195.400 ;
        RECT 65.050 195.120 67.430 195.400 ;
        RECT 68.270 195.120 70.650 195.400 ;
        RECT 71.490 195.120 73.870 195.400 ;
        RECT 74.710 195.120 77.090 195.400 ;
        RECT 77.930 195.120 80.310 195.400 ;
        RECT 81.150 195.120 83.530 195.400 ;
        RECT 84.370 195.120 86.750 195.400 ;
        RECT 87.590 195.120 89.970 195.400 ;
        RECT 90.810 195.120 93.190 195.400 ;
        RECT 94.030 195.120 96.410 195.400 ;
        RECT 97.250 195.120 99.630 195.400 ;
        RECT 100.470 195.120 102.850 195.400 ;
        RECT 103.690 195.120 106.070 195.400 ;
        RECT 106.910 195.120 109.290 195.400 ;
        RECT 110.130 195.120 112.510 195.400 ;
        RECT 113.350 195.120 115.730 195.400 ;
        RECT 116.570 195.120 118.950 195.400 ;
        RECT 119.790 195.120 122.170 195.400 ;
        RECT 123.010 195.120 125.390 195.400 ;
        RECT 126.230 195.120 128.610 195.400 ;
        RECT 129.450 195.120 131.830 195.400 ;
        RECT 132.670 195.120 135.050 195.400 ;
        RECT 135.890 195.120 138.270 195.400 ;
        RECT 139.110 195.120 144.710 195.400 ;
        RECT 145.550 195.120 183.900 195.400 ;
        RECT 4.690 4.280 183.900 195.120 ;
        RECT 4.690 3.670 32.010 4.280 ;
        RECT 32.850 3.670 35.230 4.280 ;
        RECT 36.070 3.670 38.450 4.280 ;
        RECT 39.290 3.670 44.890 4.280 ;
        RECT 45.730 3.670 48.110 4.280 ;
        RECT 48.950 3.670 51.330 4.280 ;
        RECT 52.170 3.670 54.550 4.280 ;
        RECT 55.390 3.670 57.770 4.280 ;
        RECT 58.610 3.670 60.990 4.280 ;
        RECT 61.830 3.670 64.210 4.280 ;
        RECT 65.050 3.670 67.430 4.280 ;
        RECT 68.270 3.670 70.650 4.280 ;
        RECT 71.490 3.670 73.870 4.280 ;
        RECT 74.710 3.670 77.090 4.280 ;
        RECT 77.930 3.670 80.310 4.280 ;
        RECT 81.150 3.670 83.530 4.280 ;
        RECT 84.370 3.670 86.750 4.280 ;
        RECT 87.590 3.670 89.970 4.280 ;
        RECT 90.810 3.670 93.190 4.280 ;
        RECT 94.030 3.670 96.410 4.280 ;
        RECT 97.250 3.670 99.630 4.280 ;
        RECT 100.470 3.670 102.850 4.280 ;
        RECT 103.690 3.670 106.070 4.280 ;
        RECT 106.910 3.670 109.290 4.280 ;
        RECT 110.130 3.670 112.510 4.280 ;
        RECT 113.350 3.670 115.730 4.280 ;
        RECT 116.570 3.670 118.950 4.280 ;
        RECT 119.790 3.670 122.170 4.280 ;
        RECT 123.010 3.670 125.390 4.280 ;
        RECT 126.230 3.670 128.610 4.280 ;
        RECT 129.450 3.670 131.830 4.280 ;
        RECT 132.670 3.670 135.050 4.280 ;
        RECT 135.890 3.670 138.270 4.280 ;
        RECT 139.110 3.670 141.490 4.280 ;
        RECT 142.330 3.670 183.900 4.280 ;
      LAYER met3 ;
        RECT 3.990 181.240 184.680 187.845 ;
        RECT 4.400 179.840 184.280 181.240 ;
        RECT 3.990 177.840 184.680 179.840 ;
        RECT 3.990 176.440 184.280 177.840 ;
        RECT 3.990 174.440 184.680 176.440 ;
        RECT 3.990 173.040 184.280 174.440 ;
        RECT 3.990 171.040 184.680 173.040 ;
        RECT 3.990 169.640 184.280 171.040 ;
        RECT 3.990 167.640 184.680 169.640 ;
        RECT 3.990 166.240 184.280 167.640 ;
        RECT 3.990 164.240 184.680 166.240 ;
        RECT 3.990 162.840 184.280 164.240 ;
        RECT 3.990 160.840 184.680 162.840 ;
        RECT 3.990 159.440 184.280 160.840 ;
        RECT 3.990 157.440 184.680 159.440 ;
        RECT 4.400 156.040 184.280 157.440 ;
        RECT 3.990 154.040 184.680 156.040 ;
        RECT 3.990 152.640 184.280 154.040 ;
        RECT 3.990 150.640 184.680 152.640 ;
        RECT 3.990 149.240 184.280 150.640 ;
        RECT 3.990 147.240 184.680 149.240 ;
        RECT 4.400 145.840 184.280 147.240 ;
        RECT 3.990 143.840 184.680 145.840 ;
        RECT 4.400 142.440 184.280 143.840 ;
        RECT 3.990 140.440 184.680 142.440 ;
        RECT 4.400 139.040 184.280 140.440 ;
        RECT 3.990 137.040 184.680 139.040 ;
        RECT 4.400 135.640 184.280 137.040 ;
        RECT 3.990 133.640 184.680 135.640 ;
        RECT 4.400 132.240 184.280 133.640 ;
        RECT 3.990 130.240 184.680 132.240 ;
        RECT 4.400 128.840 184.280 130.240 ;
        RECT 3.990 126.840 184.680 128.840 ;
        RECT 4.400 125.440 184.280 126.840 ;
        RECT 3.990 123.440 184.680 125.440 ;
        RECT 4.400 122.040 184.280 123.440 ;
        RECT 3.990 120.040 184.680 122.040 ;
        RECT 4.400 118.640 184.280 120.040 ;
        RECT 3.990 116.640 184.680 118.640 ;
        RECT 4.400 115.240 184.280 116.640 ;
        RECT 3.990 113.240 184.680 115.240 ;
        RECT 4.400 111.840 184.280 113.240 ;
        RECT 3.990 109.840 184.680 111.840 ;
        RECT 4.400 108.440 184.280 109.840 ;
        RECT 3.990 106.440 184.680 108.440 ;
        RECT 4.400 105.040 184.280 106.440 ;
        RECT 3.990 103.040 184.680 105.040 ;
        RECT 4.400 101.640 184.280 103.040 ;
        RECT 3.990 99.640 184.680 101.640 ;
        RECT 4.400 98.240 184.280 99.640 ;
        RECT 3.990 96.240 184.680 98.240 ;
        RECT 4.400 94.840 184.280 96.240 ;
        RECT 3.990 92.840 184.680 94.840 ;
        RECT 4.400 91.440 184.280 92.840 ;
        RECT 3.990 89.440 184.680 91.440 ;
        RECT 4.400 88.040 184.280 89.440 ;
        RECT 3.990 86.040 184.680 88.040 ;
        RECT 4.400 84.640 184.280 86.040 ;
        RECT 3.990 82.640 184.680 84.640 ;
        RECT 4.400 81.240 184.280 82.640 ;
        RECT 3.990 79.240 184.680 81.240 ;
        RECT 4.400 77.840 184.280 79.240 ;
        RECT 3.990 75.840 184.680 77.840 ;
        RECT 4.400 74.440 184.280 75.840 ;
        RECT 3.990 72.440 184.680 74.440 ;
        RECT 4.400 71.040 184.280 72.440 ;
        RECT 3.990 69.040 184.680 71.040 ;
        RECT 4.400 67.640 184.280 69.040 ;
        RECT 3.990 65.640 184.680 67.640 ;
        RECT 4.400 64.240 184.280 65.640 ;
        RECT 3.990 62.240 184.680 64.240 ;
        RECT 4.400 60.840 184.280 62.240 ;
        RECT 3.990 58.840 184.680 60.840 ;
        RECT 4.400 57.440 184.280 58.840 ;
        RECT 3.990 55.440 184.680 57.440 ;
        RECT 4.400 54.040 184.280 55.440 ;
        RECT 3.990 52.040 184.680 54.040 ;
        RECT 4.400 50.640 184.280 52.040 ;
        RECT 3.990 48.640 184.680 50.640 ;
        RECT 4.400 47.240 184.280 48.640 ;
        RECT 3.990 45.240 184.680 47.240 ;
        RECT 3.990 43.840 184.280 45.240 ;
        RECT 3.990 41.840 184.680 43.840 ;
        RECT 4.400 40.440 184.280 41.840 ;
        RECT 3.990 38.440 184.680 40.440 ;
        RECT 3.990 37.040 184.280 38.440 ;
        RECT 3.990 35.040 184.680 37.040 ;
        RECT 3.990 33.640 184.280 35.040 ;
        RECT 3.990 31.640 184.680 33.640 ;
        RECT 3.990 30.240 184.280 31.640 ;
        RECT 3.990 28.240 184.680 30.240 ;
        RECT 3.990 26.840 184.280 28.240 ;
        RECT 3.990 24.840 184.680 26.840 ;
        RECT 3.990 23.440 184.280 24.840 ;
        RECT 3.990 21.440 184.680 23.440 ;
        RECT 3.990 20.040 184.280 21.440 ;
        RECT 3.990 10.715 184.680 20.040 ;
  END
END dff_ram_4x72
END LIBRARY

